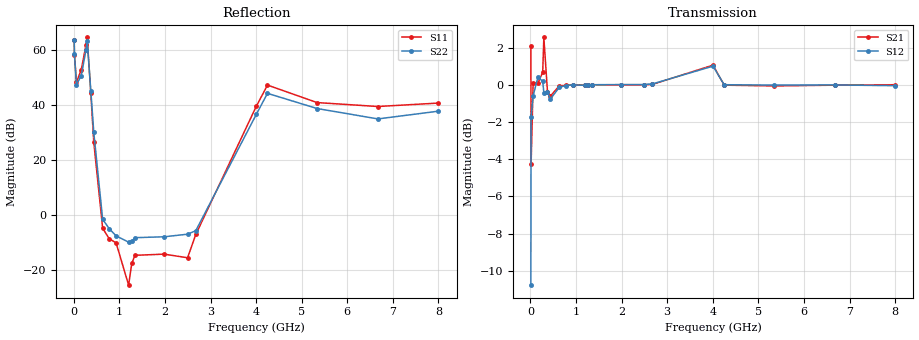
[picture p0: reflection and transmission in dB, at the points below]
!Agilent Technologies,N5230A,US43500312,A.07.50.67
!Agilent N5230A: A.07.50.67
!Date: Tuesday, June 09, 2015 15:34:24
!Correction: S11(Full 2 Port(1,2))
!S21(Full 2 Port(1,2))
!S12(Full 2 Port(1,2))
!S22(Full 2 Port(1,2))
!S2P File: Measurements: S11, S21, S12, S22:
# Hz S  MA  R 50
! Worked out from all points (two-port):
!   1601 points, 10 MHz to 8 GHz, reference 50 ohm
!   highest |S21| = 2.56 dB at 294.6 MHz (marker M1); lowest = -4.3 dB at 14.99 MHz (marker M2)
!   |S21| within 3 dB of the highest: 79.97 MHz to 171.9 MHz (91.95 MHz wide, 73 % of centre); 551.9 MHz to end of sweep (the widest 2 of 13)
!   lowest |S11| = -25.7 dB at 1.204 GHz (marker M3), VSWR 1.11, Z = 54.2 + j3.47 ohm
!   |S11| at or under -10 dB: 790.5 MHz to 935.7 MHz (145.3 MHz wide, 16.8 % of centre); 1.046 GHz to 2.088 GHz (1.042 GHz wide, 66.5 % of centre); 2.373 GHz to 2.622 GHz (248.2 MHz wide, 9.94 % of centre) (the widest 3 of 4)
!   |S22| runs from -13.9 to 63.6 dB; largest |S21 - S12| = 1.4
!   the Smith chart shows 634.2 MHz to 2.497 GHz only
!   S11 on the Smith chart (normalised r, x): 634.2 MHz: 0.39, +0.60; 779 MHz: 0.48, +0.16; 928.9 MHz: 0.93, -0.61; 1.273 GHz: 0.91, +0.23; 1.983 GHz: 0.69, +0.11; 2.497 GHz: 0.74, -0.11
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1e7  1501 171.2  1.276 -3.4  0.2893 -111.4  1520 -19.4
1.499375e7  815.1 226.2  0.6113 24.7  0.8214 4.8  827.8 32.4
5.99375e7  257.8 325.8  1.012 -4.6  0.9352 2.9  232.8 92.2
1.648062e8  434.5 400.9  1.012 2.2  1.048 0.4  337.3 123.1
2.69675e8  1223 382.5  1.081 -5.5  1.023 2.5  1002 100.3
2.946438e8  1679 409.0  1.342 8.8  0.9527 -7.0  1439 129.7
3.745438e8  161.6 432.9  0.9573 2.5  0.955 0.6  179.1 175.5
4.394625e8  20.65 412.7  0.9333 2.4  0.9166 2.5  31.41 195.2
6.342188e8  0.5643 471.8  0.9945 4.1  0.9852 4.2  0.8166 373.3
7.790375e8  0.3627 516.0  0.9968 3.2  0.9956 3.0  0.5542 453.1
9.2885e8  0.3059 640.8  1.001 3.1  1 3.1  0.4094 576.9
1.203506e9  0.05204 757.9  0.9988 3.3  0.9971 3.4  0.3148 688.9
1.273419e9  0.13 824.0  1.001 3.3  0.9999 3.4  0.328 733.0
1.343331e9  0.1814 838.2  1.001 3.3  1.001 3.3  0.38 763.2
1.982531e9  0.1906 876.8  0.999 3.1  1.002 3.1  0.3945 1030.5
2.496888e9  0.1638 927.1  1.001 3.5  1.002 3.5  0.4399 1152.6
2.676662e9  0.4342 1017.1  1.003 3.5  1.006 3.6  0.5093 1231.0
4.005e9  93.66 1392.1  1.13 -0.4  1.123 -0.1  66.8 1520.5
4.249694e9  227.4 1342.4  0.9984 -3.4  1.001 -3.8  160.8 1460.3
5.338331e9  109.3 1319.6  0.9935 0.3  0.9988 0.4  85.19 1399.7
6.671662e9  92.69 1357.5  0.9983 0.4  0.9997 0.7  55.12 1339.0
8e9  107.1 1386.1  1.001 0.5  0.9949 0.4  76.23 1307.2
